VERSION 5.7 ;
  NOWIREEXTENSIONATPIN ON ;
  DIVIDERCHAR "/" ;
  BUSBITCHARS "[]" ;
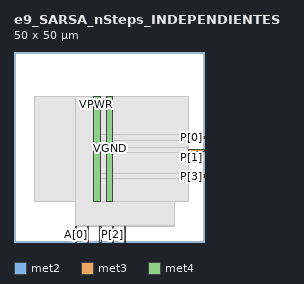
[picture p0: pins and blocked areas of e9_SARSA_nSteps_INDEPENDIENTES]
MACRO e9_SARSA_nSteps_INDEPENDIENTES
  CLASS BLOCK ;
  FOREIGN e9_SARSA_nSteps_INDEPENDIENTES ;
  ORIGIN 0.000 0.000 ;
  SIZE 50.000 BY 50.000 ;
  PIN A[0]
    DIRECTION INPUT ;
    USE SIGNAL ;
    ANTENNAGATEAREA 0.196500 ;
    PORT
      LAYER met2 ;
        RECT 16.190 0.000 16.470 4.000 ;
    END
  END A[0]
  PIN A[1]
    DIRECTION INPUT ;
    USE SIGNAL ;
    ANTENNAGATEAREA 0.196500 ;
    PORT
      LAYER met2 ;
        RECT 19.410 0.000 19.690 4.000 ;
    END
  END A[1]
  PIN B[0]
    DIRECTION INPUT ;
    USE SIGNAL ;
    ANTENNAGATEAREA 0.196500 ;
    PORT
      LAYER met2 ;
        RECT 22.630 0.000 22.910 4.000 ;
    END
  END B[0]
  PIN B[1]
    DIRECTION INPUT ;
    USE SIGNAL ;
    ANTENNAGATEAREA 0.196500 ;
    PORT
      LAYER met2 ;
        RECT 29.070 0.000 29.350 4.000 ;
    END
  END B[1]
  PIN P[0]
    DIRECTION OUTPUT ;
    USE SIGNAL ;
    ANTENNADIFFAREA 0.445500 ;
    PORT
      LAYER met3 ;
        RECT 46.000 27.240 50.000 27.840 ;
    END
  END P[0]
  PIN P[1]
    DIRECTION OUTPUT ;
    USE SIGNAL ;
    ANTENNADIFFAREA 0.445500 ;
    PORT
      LAYER met3 ;
        RECT 46.000 23.840 50.000 24.440 ;
    END
  END P[1]
  PIN P[2]
    DIRECTION OUTPUT ;
    USE SIGNAL ;
    ANTENNADIFFAREA 0.445500 ;
    PORT
      LAYER met2 ;
        RECT 25.850 0.000 26.130 4.000 ;
    END
  END P[2]
  PIN P[3]
    DIRECTION OUTPUT ;
    USE SIGNAL ;
    ANTENNADIFFAREA 0.445500 ;
    PORT
      LAYER met3 ;
        RECT 46.000 17.040 50.000 17.640 ;
    END
  END P[3]
  PIN VGND
    DIRECTION INOUT ;
    USE GROUND ;
    PORT
      LAYER met4 ;
        RECT 24.340 10.640 25.940 38.320 ;
    END
  END VGND
  PIN VPWR
    DIRECTION INOUT ;
    USE POWER ;
    PORT
      LAYER met4 ;
        RECT 21.040 10.640 22.640 38.320 ;
    END
  END VPWR
  OBS
      LAYER nwell ;
        RECT 5.330 10.795 44.350 38.165 ;
      LAYER li1 ;
        RECT 5.520 10.795 44.160 38.165 ;
      LAYER met1 ;
        RECT 5.520 10.640 44.160 38.320 ;
      LAYER met2 ;
        RECT 16.200 4.280 42.230 38.265 ;
        RECT 16.750 4.000 19.130 4.280 ;
        RECT 19.970 4.000 22.350 4.280 ;
        RECT 23.190 4.000 25.570 4.280 ;
        RECT 26.410 4.000 28.790 4.280 ;
        RECT 29.630 4.000 42.230 4.280 ;
      LAYER met3 ;
        RECT 21.050 28.240 46.000 38.245 ;
        RECT 21.050 26.840 45.600 28.240 ;
        RECT 21.050 24.840 46.000 26.840 ;
        RECT 21.050 23.440 45.600 24.840 ;
        RECT 21.050 18.040 46.000 23.440 ;
        RECT 21.050 16.640 45.600 18.040 ;
        RECT 21.050 10.715 46.000 16.640 ;
  END
END e9_SARSA_nSteps_INDEPENDIENTES
END LIBRARY

